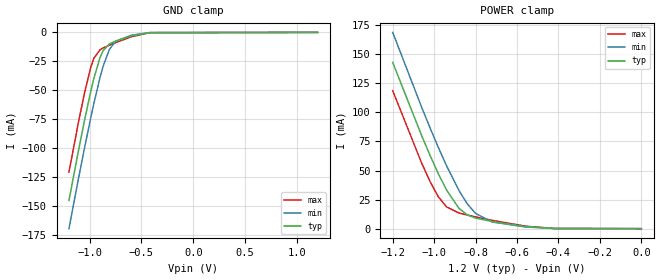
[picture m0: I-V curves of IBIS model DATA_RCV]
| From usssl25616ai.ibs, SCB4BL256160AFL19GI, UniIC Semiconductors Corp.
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|   Model DATA_RCV
[Model]  DATA_RCV
Model_type Input
Polarity   Non-Inverting
Enable   Active-High
Vinl =   0.3800V
Vinh =   0.8200V
C_comp   1.7430pF   1.7110pF   1.7640pF
[Temperature Range]   25.0000   85.0000   -40.0000
[Voltage Range]   1.2000V   1.1400V   1.3000V
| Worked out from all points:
|   GND clamp passes 1 mA (typ) near -0.50 V on its own axis
|   POWER clamp passes 1 mA (typ) near -0.51 V on its own axis
[GND_clamp]
|Voltage   I(typ)   I(min)   I(max)
-1.2V     -145.3mA   -169.7mA   -120.8mA
-1.11V    -103.1mA   -127.3mA   -78.51mA
-1.05V    -76.2mA    -100.1mA   -52.43mA
-990mV    -51.2mA    -74mA      -30.39mA
-960mV    -39.9mA    -61.63mA   -22.48mA
-900mV    -21.67mA   -39mA      -15mA
-870mV    -15.78mA   -29.25mA   -13.45mA
-810mV    -10.04mA   -14.72mA   -11.07mA
-750mV    -7.557mA   -7.71mA    -8.865mA
-600mV    -3.111mA   -2.463mA   -3.804mA
-420mV    -215.4uA   -156.1uA   -235uA
1.2V      1.597nA    5.589nA    1.463nA
[POWER_clamp]
|Voltage   I(typ)   I(min)   I(max)
-1.2V     143mA      168.8mA    118.7mA
-1.06V    79.88mA    104.3mA    56.26mA
-1.02V    63.08mA    86.79mA    40.63mA
-980mV    47.32mA    69.97mA    27.48mA
-940mV    33.2mA     54.05mA    18.67mA
-880mV    17.43mA    32.78mA    13.45mA
-840mV    11.87mA    21.34mA    11.69mA
-800mV    9.133mA    13.1mA     10.12mA
-720mV    6.135mA    5.731mA    7.166mA
-560mV    1.838mA    1.456mA    2.161mA
-420mV    156.9uA    132.7uA    153uA
0V        1.597nA    1.927nA    2.16nA
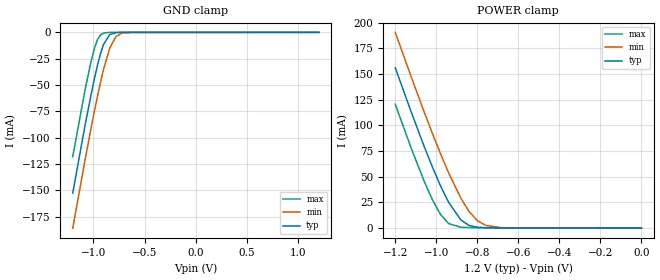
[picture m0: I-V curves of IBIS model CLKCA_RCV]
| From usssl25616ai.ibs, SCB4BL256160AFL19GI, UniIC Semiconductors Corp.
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|   Model CLKCA_RCV
[Model]  CLKCA_RCV
Model_type Input
Polarity   Non-Inverting
Enable   Active-High
Vinl =   0.3800V
Vinh =   0.8200V
C_comp   1.2950pF   1.2730pF   1.3120pF
[Temperature Range]   25.0000   85.0000   -40.0000
[Voltage Range]   1.2000V   1.1400V   1.3000V
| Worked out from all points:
|   GND clamp passes 1 mA (typ) near -0.82 V on its own axis
|   POWER clamp passes 1 mA (typ) near -0.80 V on its own axis
[GND_clamp]
|Voltage   I(typ)   I(min)   I(max)
-1.2V     -152.5mA   -185.8mA   -117.9mA
-1.08V    -88.17mA   -121mA     -54.47mA
-1.02V    -58.29mA   -90.1mA    -26.85mA
-990mV    -44.4mA    -75.3mA    -15.51mA
-960mV    -31.61mA   -61.08mA   -7.11mA
-930mV    -20.41mA   -47.63mA   -2.43mA
-900mV    -11.47mA   -35.22mA   -660.1uA
-840mV    -2.135mA   -15.11mA   -38.7uA
-780mV    -251.2uA   -4.07mA    -2.167uA
-720mV    -26.67uA   -738uA     -121.2nA
-630mV    -905.5nA   -45.69uA   -1.763nA
1.2V      454.1pA    528.1pA    490.2pA
[POWER_clamp]
|Voltage   I(typ)   I(min)   I(max)
-1.2V     156.1mA    190.5mA    120.5mA
-1.12V    111.8mA    146mA      76.62mA
-1.06V    80.05mA    113.6mA    46.08mA
-1.02V    59.99mA    92.74mA    28.04mA
-980mV    41.4mA     72.69mA    13.46mA
-940mV    25.12mA    53.83mA    4.459mA
-880mV    7.896mA    29.03mA    846.4uA
-840mV    2.639mA    16.14mA    544.2uA
-800mV    870.9uA    7.332mA    436.1uA
-760mV    394.4uA    2.735mA    358uA
-680mV    180.2uA    359uA      223.2uA
0V        454.1pA    322.3pA    727.1pA
